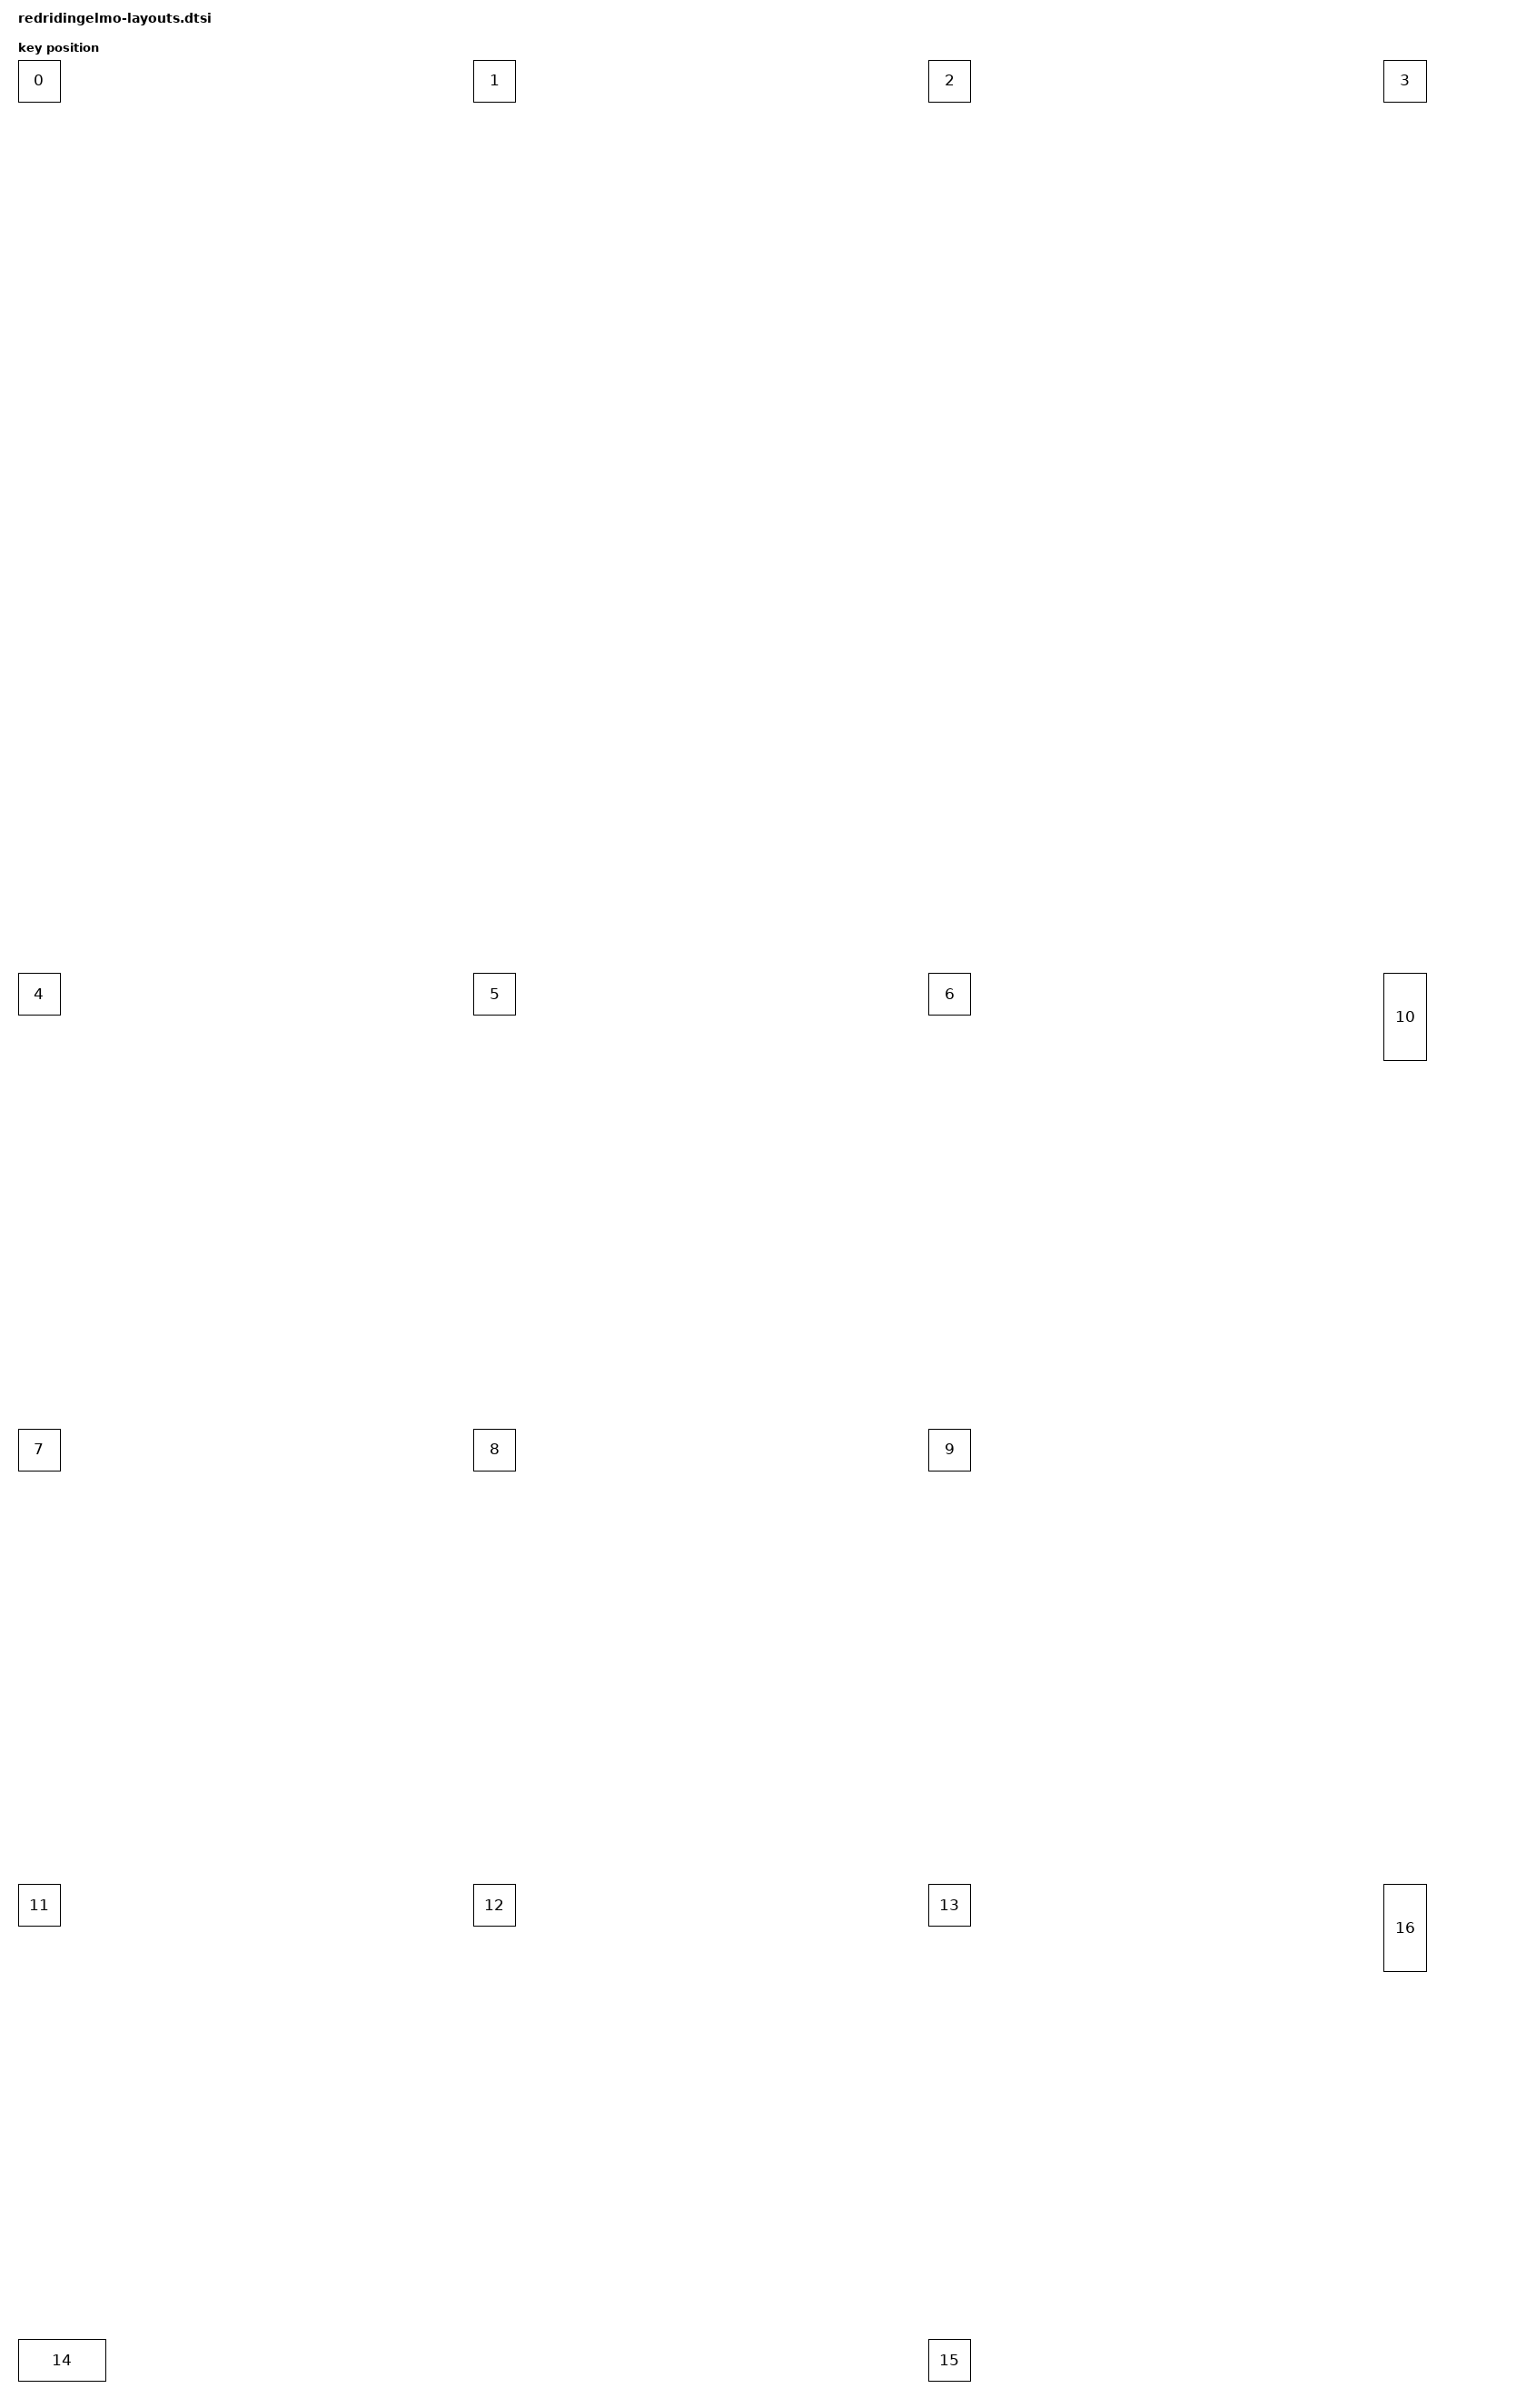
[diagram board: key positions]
#include <physical_layouts.dtsi>

/ {
    default_transform: transform_0 {
        compatible = "zmk,layout-transform";
        status = "okay";
        matrix = <1 0 0 1 0 0>;
        map = <0 1 2 3 4 5 6 7 8 9 10 11 12 13 14 15 16>;
    };

    redridingelmo_physical_layout: redridingelmo_physical_layout {
        compatible = "zmk,physical-layout";
        display-name = "redridingelmo";
        transform = <&default_transform>;
        kscan = <&kscan0>;
        keys =
            // row col           w    h      x      y   rot rx ry
            <&key_physical_attrs 100 100     0   112   0 0 0>   // 0 0
          , <&key_physical_attrs 100 100  1003   112   0 0 0>   // 0 1
          , <&key_physical_attrs 100 100  2005   112   0 0 0>   // 0 2
          , <&key_physical_attrs 100 100  3008   112   0 0 0>   // 0 3

          , <&key_physical_attrs 100 100     0  2123   0 0 0>   // 1 0
          , <&key_physical_attrs 100 100  1003 2123   0 0 0>   // 1 1
          , <&key_physical_attrs 100 100  2005 2123   0 0 0>   // 1 2

          , <&key_physical_attrs 100 100     0 3126   0 0 0>   // 2 0
          , <&key_physical_attrs 100 100  1003 3126   0 0 0>   // 2 1
          , <&key_physical_attrs 100 100  2005 3126   0 0 0>   // 2 2
          , <&key_physical_attrs 100 200  3008 2123   0 0 0>   // 2 3, h:2

          , <&key_physical_attrs 100 100     0 4129   0 0 0>   // 3 0
          , <&key_physical_attrs 100 100  1003 4129   0 0 0>   // 3 1
          , <&key_physical_attrs 100 100  2005 4129   0 0 0>   // 3 2

          , <&key_physical_attrs 200 100     1 5131   0 0 0>   // 4 0, u:2
          , <&key_physical_attrs 100 100  2005 5131   0 0 0>   // 4 1
          , <&key_physical_attrs 100 200  3008 4129   0 0 0>   // 4 2, h:2
            ;
    };
};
